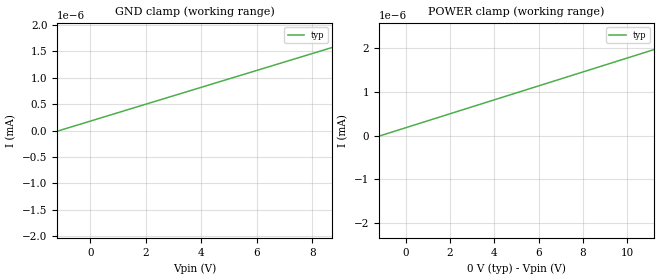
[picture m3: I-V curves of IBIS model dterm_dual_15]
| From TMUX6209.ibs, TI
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| dterm_dual_15
[Model]   dterm_dual_15
Model_type   Terminator
|   typ   min   max
C_comp   4.014581e-11   NA   NA
[Voltage Range]   0   -15   15
[Temperature Range]   27   NA   NA
[Power Clamp Reference]   0   NA   NA
[GND Clamp Reference]   0   NA   NA
[GND Clamp]
|   Voltage   I(typ)   I(min)   I(max)
-20V      -4.608A    NA         NA
-13.28V   -1.964nA   NA         NA
11.11V    1.955nA    NA         NA
15V       2.581nA    NA         NA
[POWER Clamp]
|   Voltage   I(typ)   I(min)   I(max)
-15V      -2.247nA   NA         NA
-4.747V   -582.5pA   NA         NA
14.34V    2.472nA    NA         NA
20V       5.407A     NA         NA
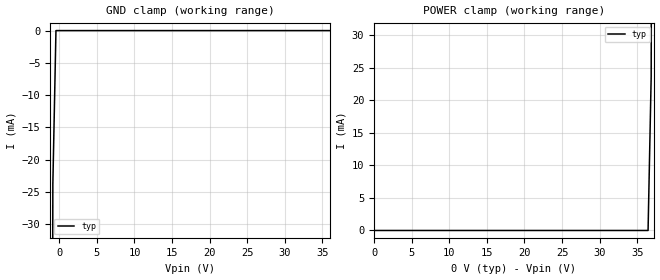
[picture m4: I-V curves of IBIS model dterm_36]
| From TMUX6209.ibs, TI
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| dterm_36
[Model]   dterm_36
Model_type   Terminator
|   typ   min   max
C_comp   4.014581e-11   NA   NA
[Voltage Range]   36   0   36
[Temperature Range]   27   NA   NA
[Power Clamp Reference]   0   NA   NA
[GND Clamp Reference]   0   NA   NA
[GND Clamp]
|   Voltage   I(typ)   I(min)   I(max)
-5V       -4.616A    NA         NA
-1.273V   -287.8mA   NA         NA
-858.6mV  -23.82mA   NA         NA
-444.4mV  -1.609uA   NA         NA
36V       3.101nA    NA         NA
[POWER Clamp]
|   Voltage   I(typ)   I(min)   I(max)
0V        -2.72nA    NA         NA
36.44V    2.034uA    NA         NA
36.86V    23.64mA    NA         NA
37.27V    271.7mA    NA         NA
41V       5.411A     NA         NA
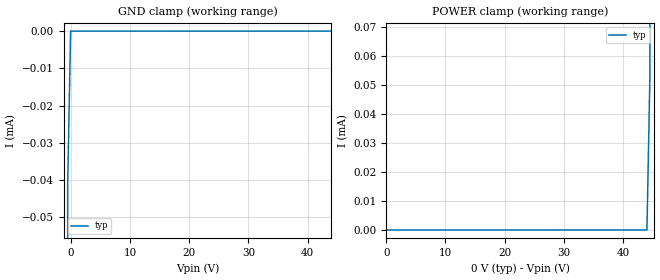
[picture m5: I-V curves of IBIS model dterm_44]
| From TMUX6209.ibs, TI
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| dterm_44
[Model]   dterm_44
Model_type   Terminator
|   typ   min   max
C_comp   4.014581e-11   NA   NA
[Voltage Range]   44   0   44
[Temperature Range]   27   NA   NA
[Power Clamp Reference]   0   NA   NA
[GND Clamp Reference]   0   NA   NA
[GND Clamp]
|   Voltage   I(typ)   I(min)   I(max)
-5V       -4.624A    NA         NA
-1.04V    -123.2mA   NA         NA
-545.5mV  -41.1uA    NA         NA
-50.51mV  -3.399nA   NA         NA
44V       3.798nA    NA         NA
[POWER Clamp]
|   Voltage   I(typ)   I(min)   I(max)
0V        -3.369nA   NA         NA
44.05V    3.816nA    NA         NA
44.55V    52.87uA    NA         NA
45.04V    121.7mA    NA         NA
49V       5.416A     NA         NA
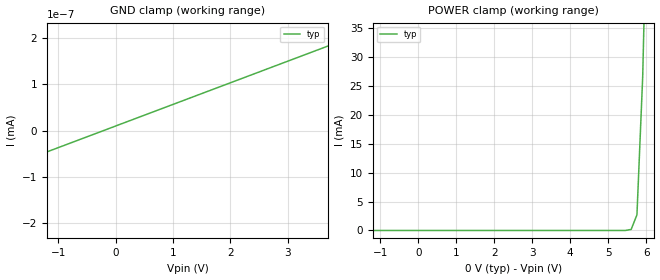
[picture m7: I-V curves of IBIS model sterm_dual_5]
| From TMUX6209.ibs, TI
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| sterm_dual_5
[Model]   sterm_dual_5
Model_type   Terminator
|   typ   min   max
C_comp   1.008417e-11   NA   NA
[Voltage Range]   0   -5   5
[Temperature Range]   27   NA   NA
[Power Clamp Reference]   0   NA   NA
[GND Clamp Reference]   0   NA   NA
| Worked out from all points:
|   GND clamp passes 1 mA (typ) near -5.65 V on its own axis
[GND Clamp]
|   Voltage   I(typ)   I(min)   I(max)
-10V      -1.582A    NA         NA
-5V       -225pA     NA         NA
4.545V    222.9pA    NA         NA
5V        245.2pA    NA         NA
[POWER Clamp]
|   Voltage   I(typ)   I(min)   I(max)
-5V       -225pA     NA         NA
5.455V    2.308uA    NA         NA
5.606V    186uA      NA         NA
5.758V    2.717mA    NA         NA
5.909V    26.59mA    NA         NA
6.061V    69.04mA    NA         NA
10V       3.275A     NA         NA
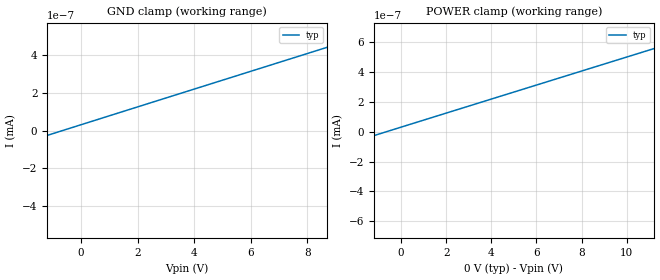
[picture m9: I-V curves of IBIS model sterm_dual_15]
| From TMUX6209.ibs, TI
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| sterm_dual_15
[Model]   sterm_dual_15
Model_type   Terminator
|   typ   min   max
C_comp   1.008417e-11   NA   NA
[Voltage Range]   0   -15   15
[Temperature Range]   27   NA   NA
[Power Clamp Reference]   0   NA   NA
[GND Clamp Reference]   0   NA   NA
[GND Clamp]
|   Voltage   I(typ)   I(min)   I(max)
-20V      -1.602A    NA         NA
-12.22V   -549.3pA   NA         NA
10.76V    535.9pA    NA         NA
11.11V    552.5pA    NA         NA
15V       736.3pA    NA         NA
[POWER Clamp]
|   Voltage   I(typ)   I(min)   I(max)
-15V      -683.8pA   NA         NA
-4.04V    -159.9pA   NA         NA
13.99V    687.5pA    NA         NA
14.34V    704.2pA    NA         NA
20V       3.299A     NA         NA
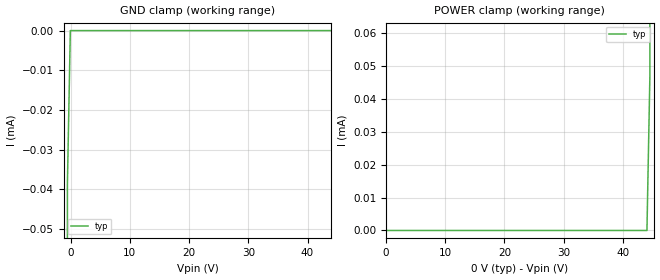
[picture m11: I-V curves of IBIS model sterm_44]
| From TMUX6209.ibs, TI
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| sterm_44
[Model]   sterm_44
Model_type   Terminator
|   typ   min   max
C_comp   6.362683e-12   NA   NA
[Voltage Range]   44   0   44
[Temperature Range]   27   NA   NA
[Power Clamp Reference]   0   NA   NA
[GND Clamp Reference]   0   NA   NA
[GND Clamp]
|   Voltage   I(typ)   I(min)   I(max)
-5V       -1.611A    NA         NA
-1.04V    -63.45mA   NA         NA
-545.5mV  -38.76uA   NA         NA
-50.51mV  -1.036nA   NA         NA
44V       1.081nA    NA         NA
[POWER Clamp]
|   Voltage   I(typ)   I(min)   I(max)
0V        -1.026nA   NA         NA
44.05V    1.087nA    NA         NA
44.55V    46.71uA    NA         NA
45.04V    85.08mA    NA         NA
49V       3.31A      NA         NA
